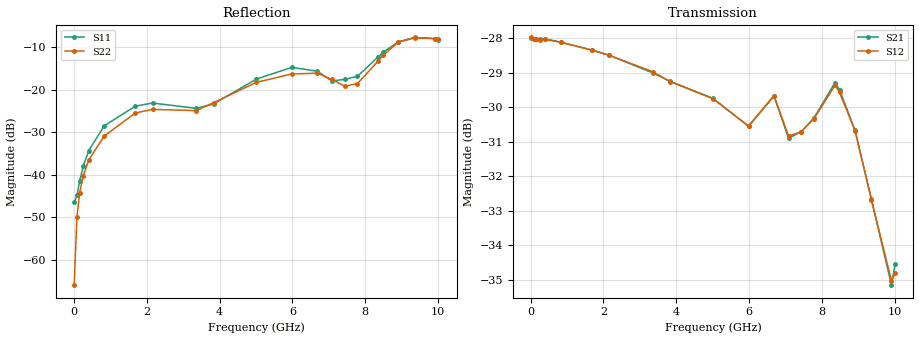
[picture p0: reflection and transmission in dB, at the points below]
! Device ID: PE43705
! Serial: 1
! Insertion: A
! Impedance: 50 ohm
! Temp: 25C
! VDD: 3.400V
! Attenuation Step: 27.00dB
#  Hz  S  RI  R  50
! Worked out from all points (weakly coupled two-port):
!   401 points, 10 MHz to 10.01 GHz, reference 50 ohm
!   highest |S21| = -27.99 dB at 10 MHz (marker M1); lowest = -35.1 dB at 9.91 GHz (marker M2)
!   lowest |S11| = -46.6 dB at 10 MHz (marker M3), VSWR 1.01, Z = 49.5 + j0.0502 ohm
!   |S11| at or under -10 dB: start of sweep to 8.671 GHz
!   |S22| runs from -66.0 to -7.8 dB; largest |S21 - S12| = 0.00068
!   S11 on the Smith chart (normalised r, x): 10 MHz: 0.99, +0.00; 7.435 GHz: 0.82, +0.16; 8.485 GHz: 0.84, +0.49; 9.36 GHz: 0.55, +0.49; 10.01 GHz: 0.49, +0.27
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1e7  -0.00467 0.000507  0.0398 -9.86e-05  0.0399 -0.000131  -0.000101 0.00049
8.5e7  -0.00442 0.00355  0.0397 -0.000925  0.0397 -0.000913  0.000444 0.00316
1.6e8  -0.00477 0.00693  0.0397 -0.00167  0.0397 -0.00163  0.000221 0.00609
2.6e8  -0.00595 0.0111  0.0396 -0.0027  0.0395 -0.00265  -0.000863 0.00969
4.1e8  -0.00888 0.017  0.0395 -0.00395  0.0394 -0.00418  -0.00357 0.0144
8.35e8  -0.0258 0.0271  0.0384 -0.0082  0.0384 -0.00811  -0.0183 0.0217
1.685e9  -0.0612 0.0177  0.035 -0.0154  0.035 -0.0154  -0.0515 0.0118
2.16e9  -0.0693 0.00429  0.0325 -0.0189  0.0325 -0.0189  -0.0584 0.000776
3.36e9  -0.0599 0.00486  0.0246 -0.0255  0.0247 -0.0256  -0.0563 0.00491
3.835e9  -0.0624 0.0263  0.0214 -0.027  0.0215 -0.0269  -0.0672 0.0197
5.01e9  -0.0991 0.0883  0.0148 -0.029  0.0149 -0.0289  -0.1057 0.0598
5.985e9  -0.1505 0.1033  0.00851 -0.0284  0.00869 -0.0284  -0.1321 0.0763
6.685e9  -0.1416 0.0827  0.00621 -0.0322  0.00606 -0.0323  -0.1385 0.0711
7.085e9  -0.1083 0.0649  0.000304 -0.0285  0.000462 -0.0287  -0.1082 0.0744
7.435e9  -0.0893 0.0967  0.00148 -0.0291  0.00157 -0.0291  -0.0731 0.0815
7.785e9  -0.0433 0.1364  0.00128 -0.0305  0.00147 -0.0304  -0.0468 0.1076
8.36e9  -0.00914 0.2431  -0.00789 -0.0334  -0.00735 -0.0332  -0.0333 0.2151
8.485e9  -0.0151 0.2726  -0.00987 -0.032  -0.00955 -0.0318  -0.041 0.2485
8.91e9  -0.0713 0.3577  -0.014 -0.0257  -0.0139 -0.0257  -0.103 0.3462
9.36e9  -0.1712 0.3733  -0.0128 -0.0194  -0.0129 -0.0193  -0.1961 0.3539
9.91e9  -0.2894 0.2711  -0.00477 -0.0168  -0.00461 -0.0171  -0.3275 0.2253
1.001e10  -0.3023 0.2366  -0.00355 -0.0184  -0.00305 -0.0179  -0.3437 0.1859
